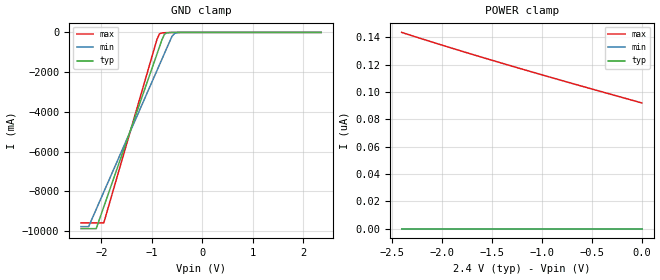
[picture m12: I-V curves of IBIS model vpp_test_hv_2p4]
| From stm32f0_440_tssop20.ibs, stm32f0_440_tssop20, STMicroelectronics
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|   Model vpp_test_hv_2p4
[Model]  vpp_test_hv_2p4
Model_type Input
Polarity   Non-Inverting
Vinl =   0.720000V
Vinh =   1.680000V
C_comp   2.584600pF   2.525900pF   2.675100pF
[Temperature Range]   25.000000   0.125000k   -40.000000
[Pullup Reference]   2.400000V   2.000000V   2.700000V
[Pulldown Reference]   0.0V   0.0V   0.0V
[POWER Clamp Reference]   2.400000V   2.000000V   2.700000V
[GND Clamp Reference]   0.0V   0.0V   0.0V
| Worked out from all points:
|   GND clamp passes 1 mA (typ) near -0.50 V on its own axis
[GND_clamp]
|Voltage   I(typ)   I(min)   I(max)
-2.4V     -9.882A    -9.779A    -9.591A
-2.25V    -9.882A    -9.779A    -9.591A
-2.1V     -9.882A    -8.907A    -9.591A
-1.95V    -8.784A    -8.035A    -9.591A
-900mV    -1.108A    -1.933A    -370.5mA
-850mV    -742.7mA   -1.642A    -75.94mA
-750mV    -94.42mA   -1.06A     -17.7mA
-700mV    -21.44mA   -769.8mA   -12.34mA
-600mV    -3.663mA   -196.9mA   -5.302mA
-550mV    -1.957mA   -54.64mA   -3.016mA
-500mV    -907.8uA   -14.15mA   -1.362mA
2.35V     0A         0A         84.79nA
[POWER_clamp]
|Voltage   I(typ)   I(min)   I(max)
-2.4V     0A         0A         143.7nA
-1.92V    0A         0A         132.6nA
-1.35V    0A         0A         120.1nA
-810mV    0A         0A         108.7nA
0V        0A         0A         92.06nA
